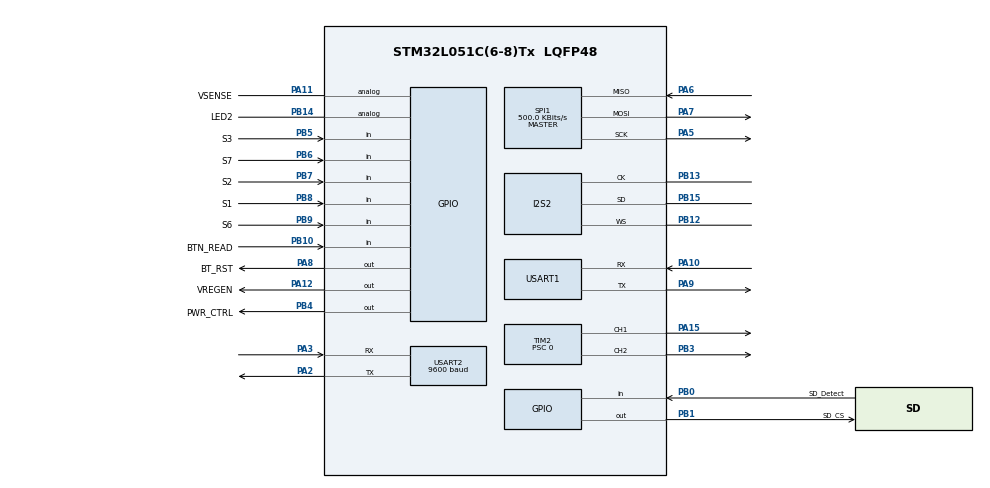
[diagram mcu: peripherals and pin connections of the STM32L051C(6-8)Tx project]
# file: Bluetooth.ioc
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Dma.Request0=SPI1_RX
Dma.Request1=SPI2_TX
Dma.SPI1_RX.0.Direction=DMA_PERIPH_TO_MEMORY
Dma.SPI1_RX.0.Instance=DMA1_Channel2
Dma.SPI1_RX.0.MemDataAlignment=DMA_MDATAALIGN_BYTE
Dma.SPI1_RX.0.MemInc=DMA_MINC_ENABLE
Dma.SPI1_RX.0.Mode=DMA_NORMAL
Dma.SPI1_RX.0.PeriphDataAlignment=DMA_PDATAALIGN_BYTE
Dma.SPI1_RX.0.PeriphInc=DMA_PINC_DISABLE
Dma.SPI1_RX.0.Priority=DMA_PRIORITY_HIGH
Dma.SPI2_TX.1.Direction=DMA_MEMORY_TO_PERIPH
Dma.SPI2_TX.1.Instance=DMA1_Channel5
Dma.SPI2_TX.1.MemDataAlignment=DMA_MDATAALIGN_BYTE
Dma.SPI2_TX.1.MemInc=DMA_MINC_ENABLE
Dma.SPI2_TX.1.Mode=DMA_NORMAL
Dma.SPI2_TX.1.PeriphDataAlignment=DMA_PDATAALIGN_BYTE
Dma.SPI2_TX.1.PeriphInc=DMA_PINC_DISABLE
Dma.SPI2_TX.1.Priority=DMA_PRIORITY_HIGH
FATFS._FS_MINIMIZE=0
FATFS._USE_MKFS=0
I2S2.AudioFreq=I2S_AUDIOFREQ_44K
I2S2.ErrorAudioFreq=-5.3 %
I2S2.Instance=SPI$Index
I2S2.RealAudioFreq=41.666 KHz
I2S2.Standard=I2S_STANDARD_PCM_SHORT
I2S2.VirtualMode=I2S_MODE_SLAVE
Mcu.Family=STM32L0
Mcu.Name=STM32L051C(6-8)Tx
Mcu.Package=LQFP48
NVIC.DMA1_Channel2_3_IRQn=true\:0\:0\:false\:false\:true\:false
NVIC.DMA1_Channel4_5_6_7_IRQn=true\:0\:0\:false\:false\:true\:false
NVIC.TIM2_IRQn=true\:0\:0\:false\:false\:true\:true
NVIC.USART1_IRQn=true\:0\:0\:false\:false\:true\:true
PA10.Mode=Asynchronous
PA10.Signal=USART1_RX
PA11.GPIO_Label=VSENSE
PA11.Signal=GPIO_Analog
PA12.GPIO_Label=VREGEN
PA12.Signal=GPIO_Output
PA13.Mode=Serial_Wire
PA13.Signal=SYS_SWDIO
PA14.Mode=Serial_Wire
PA14.Signal=SYS_SWCLK
PA15.Signal=S_TIM2_CH1
PA2.Mode=Asynchronous
PA2.Signal=USART2_TX
PA3.Mode=Asynchronous
PA3.Signal=USART2_RX
PA5.Mode=Full_Duplex_Master
PA5.Signal=SPI1_SCK
PA6.Mode=Full_Duplex_Master
PA6.Signal=SPI1_MISO
PA7.Mode=Full_Duplex_Master
PA7.Signal=SPI1_MOSI
PA8.GPIO_Label=BT_RST
PA8.Signal=GPIO_Output
PA9.Mode=Asynchronous
PA9.Signal=USART1_TX
PB0.GPIO_Label=SD_Detect
PB0.GPIO_PuPd=GPIO_PULLUP
PB0.Signal=GPIO_Input
PB1.GPIO_Label=SD_CS
PB1.PinState=GPIO_PIN_RESET
PB1.Signal=GPIO_Output
PB10.GPIO_Label=BTN_READ
PB10.GPIO_PuPd=GPIO_PULLUP
PB10.Signal=GPIO_Input
PB12.Mode=Half_Duplex_Slave
PB12.Signal=I2S2_WS
PB13.Mode=Half_Duplex_Slave
PB13.Signal=I2S2_CK
PB14.GPIO_Label=LED2
PB14.Signal=GPIO_Analog
PB15.Mode=Half_Duplex_Slave
PB15.Signal=I2S2_SD
PB3.Signal=S_TIM2_CH2
PB4.GPIO_Label=PWR_CTRL
PB4.Signal=GPIO_Output
PB5.GPIO_Label=S3
PB5.GPIO_PuPd=GPIO_PULLDOWN
PB5.Signal=GPIO_Input
PB6.GPIO_Label=S7
PB6.GPIO_PuPd=GPIO_PULLDOWN
PB6.Signal=GPIO_Input
PB7.GPIO_Label=S2
PB7.GPIO_PuPd=GPIO_PULLDOWN
PB7.Signal=GPIO_Input
PB8.GPIO_Label=S1
PB8.GPIO_PuPd=GPIO_PULLDOWN
PB8.Signal=GPIO_Input
PB9.GPIO_Label=S6
PB9.GPIO_PuPd=GPIO_PULLDOWN
PB9.Signal=GPIO_Input
ProjectManager.HeapSize=0x200
ProjectManager.StackSize=0x400
ProjectManager.TargetToolchain=TrueSTUDIO
RCC.ADCFreq_Value=4000000
RCC.AHBFreq_Value=8000000
RCC.APB1Freq_Value=8000000
RCC.APB1TimFreq_Value=8000000
RCC.APB2Freq_Value=8000000
RCC.APB2TimFreq_Value=8000000
RCC.HCLKFreq_Value=8000000
RCC.HSE_VALUE=8000000
RCC.HSI16_VALUE=16000000
RCC.HSIRCDiv=4
RCC.HSI_VALUE=4000000
RCC.LSE_VALUE=32768
RCC.MSI_VALUE=2097000
RCC.PLLMUL=RCC_PLLMUL_4
RCC.SYSCLKFreq_VALUE=8000000
RCC.SYSCLKSource=RCC_SYSCLKSOURCE_PLLCLK
RCC.VCOOutputFreq_Value=16000000
SH.S_TIM2_CH1.0=TIM2_CH1,PWM Generation1 CH1
SH.S_TIM2_CH2.0=TIM2_CH2,PWM Generation2 CH2
SPI1.BaudRatePrescaler=SPI_BAUDRATEPRESCALER_16
SPI1.CalculateBaudRate=500.0 KBits/s
SPI1.Direction=SPI_DIRECTION_2LINES
SPI1.Mode=SPI_MODE_MASTER
SPI1.VirtualType=VM_MASTER
TIM2.AutoReloadPreload=TIM_AUTORELOAD_PRELOAD_ENABLE
TIM2.Channel-PWM\ Generation1\ CH1=TIM_CHANNEL_1
TIM2.Channel-PWM\ Generation2\ CH2=TIM_CHANNEL_2
TIM2.OCMode_PWM-PWM\ Generation1\ CH1=TIM_OCMODE_PWM1
TIM2.Period=799
TIM2.Prescaler=0
TIM2.Pulse-PWM\ Generation1\ CH1=10
TIM2.Pulse-PWM\ Generation2\ CH2=10
USART1.VirtualMode-Asynchronous=VM_ASYNC
USART2.BaudRate=9600
USART2.VirtualMode-Asynchronous=VM_ASYNC
VP_FATFS_VS_Generic.Mode=User_defined
VP_TIM2_VS_ClockSourceINT.Mode=Internal
board=custom

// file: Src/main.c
/* USER CODE BEGIN Header */
/**
  ******************************************************************************
  * @file           : main.c
  * @brief          : Main program body
  ******************************************************************************
  * This notice applies to any and all portions of this file
  * that are not between comment pairs USER CODE BEGIN and
  * USER CODE END. Other portions of this file, whether
  * inserted by the user or by software development tools
  * are owned by their respective copyright owners.
  *
  * Copyright (c) 2019 STMicroelectronics International N.V.
  * All rights reserved.
  *
  * Redistribution and use in source and binary forms, with or without
  * modification, are permitted, provided that the following conditions are met:
  *
  * 1. Redistribution of source code must retain the above copyright notice,
  *    this list of conditions and the following disclaimer.
  * 2. Redistributions in binary form must reproduce the above copyright notice,
  *    this list of conditions and the following disclaimer in the documentation
  *    and/or other materials provided with the distribution.
  * 3. Neither the name of STMicroelectronics nor the names of other
  *    contributors to this software may be used to endorse or promote products
  *    derived from this software without specific written permission.
  * 4. This software, including modifications and/or derivative works of this
  *    software, must execute solely and exclusively on microcontroller or
  *    microprocessor devices manufactured by or for STMicroelectronics.
  * 5. Redistribution and use of this software other than as permitted under
  *    this license is void and will automatically terminate your rights under
  *    this license.
  *
  * THIS SOFTWARE IS PROVIDED BY STMICROELECTRONICS AND CONTRIBUTORS "AS IS"
  * AND ANY EXPRESS, IMPLIED OR STATUTORY WARRANTIES, INCLUDING, BUT NOT
  * LIMITED TO, THE IMPLIED WARRANTIES OF MERCHANTABILITY, FITNESS FOR A
  * PARTICULAR PURPOSE AND NON-INFRINGEMENT OF THIRD PARTY INTELLECTUAL PROPERTY
  * RIGHTS ARE DISCLAIMED TO THE FULLEST EXTENT PERMITTED BY LAW. IN NO EVENT
  * SHALL STMICROELECTRONICS OR CONTRIBUTORS BE LIABLE FOR ANY DIRECT, INDIRECT,
  * INCIDENTAL, SPECIAL, EXEMPLARY, OR CONSEQUENTIAL DAMAGES (INCLUDING, BUT NOT
  * LIMITED TO, PROCUREMENT OF SUBSTITUTE GOODS OR SERVICES; LOSS OF USE, DATA,
  * OR PROFITS; OR BUSINESS INTERRUPTION) HOWEVER CAUSED AND ON ANY THEORY OF
  * LIABILITY, WHETHER IN CONTRACT, STRICT LIABILITY, OR TORT (INCLUDING
  * NEGLIGENCE OR OTHERWISE) ARISING IN ANY WAY OUT OF THE USE OF THIS SOFTWARE,
  * EVEN IF ADVISED OF THE POSSIBILITY OF SUCH DAMAGE.
  *
  ******************************************************************************
  */
/* USER CODE END Header */

#include "main.h"

/* USER CODE BEGIN Includes */
#include <stdio.h>
#include <string.h>
#include <stdint.h>
#include "globals.h"
#include "AudioFile.h"
#include "fatfs.h"
#include "userInputs.h"
#include "stm32l0xx_hal.h"
#include "states.h"
#include "LEDControl.h"

/* USER CODE END Includes */

/* USER CODE BEGIN PV */
uint8_t usart1data;
uint8_t usart2data;
uint8_t bc127DataBuff[100];
uint8_t bc127DataBuffCt = 0;
uint8_t pcDataBuff[100];
uint8_t pcDataBuffCt = 0;
uint32_t initTickCount;
WAVaudioFile WAVfile;
bc127Device_t bc127Device;

bc127Notification_e Notification = INIT_STATE;
bc127Status_e Status = NOT_READY;

/* USER CODE END PV */

void SystemClock_Config(void);
static void MX_GPIO_Init(void);
static void MX_DMA_Init(void);
static void MX_SPI1_Init(void);
static void MX_I2S2_Init(void);
static void MX_USART1_UART_Init(void);
static void MX_USART2_UART_Init(void);
static void MX_TIM2_Init(void);
static void ADC_Init(void);

int main(void)
{

  /* MCU Configuration--------------------------------------------------------*/

  /* Reset of all peripherals, Initializes the Flash interface and the Systick. */
  HAL_Init();

  /* Configure the system clock */
  SystemClock_Config();

  /* Initialize all configured peripherals */
  MX_GPIO_Init();
  HAL_GPIO_WritePin(GPIOA,BT_RST_Pin,GPIO_PIN_SET); //this may be too late, may have to move this up as early as possible
  MX_DMA_Init();
  MX_SPI1_Init();
  MX_I2S2_Init();
  MX_USART1_UART_Init();
  MX_USART2_UART_Init();
  MX_FATFS_Init();
  MX_TIM2_Init();
  ADC_Init();

  /* USER CODE BEGIN 2 */
  timedStartup();
  sdInit();
  /* USER CODE END 2 */

  /* Infinite loop */
  while (1)
  {

    /* USER CODE BEGIN 3 */
	  runStates(&WAVfile, &bc127Device);

	  LEDBlinkControl(&bc127Device);

	  if(HAL_GPIO_ReadPin(GPIOB,BTN_READ_Pin) == GPIO_PIN_RESET){
			 HAL_GPIO_WritePin(GPIOB,PWR_CTRL_Pin,GPIO_PIN_RESET);
	  }

	  usartHandler();
	  bc127UartHandler();
	  bc127Read(&bc127Device);
	  checkButtonPresses();
  }
  /* USER CODE END 3 */
}

void SystemClock_Config(void)
{
  RCC_OscInitTypeDef RCC_OscInitStruct = {0};
  RCC_ClkInitTypeDef RCC_ClkInitStruct = {0};
  RCC_PeriphCLKInitTypeDef PeriphClkInit = {0};

  /**Configure the main internal regulator output voltage
  */
  __HAL_PWR_VOLTAGESCALING_CONFIG(PWR_REGULATOR_VOLTAGE_SCALE1);
  /**Initializes the CPU, AHB and APB busses clocks
  */
  RCC_OscInitStruct.OscillatorType = RCC_OSCILLATORTYPE_HSI;
  //RCC_OscInitStruct.HSIState = RCC_HSI_DIV4;
  RCC_OscInitStruct.HSIState = RCC_HSI_ON;
  RCC_OscInitStruct.HSICalibrationValue = RCC_HSICALIBRATION_DEFAULT;
  RCC_OscInitStruct.PLL.PLLState = RCC_PLL_ON;
  RCC_OscInitStruct.PLL.PLLSource = RCC_PLLSOURCE_HSI;
  RCC_OscInitStruct.PLL.PLLMUL = RCC_PLLMUL_6;
  RCC_OscInitStruct.PLL.PLLDIV = RCC_PLLDIV_4;
  //RCC_OscInitStruct.PLL.PLLDIV = RCC_PLLDIV_4; //this combined with HSI state brings f to 16MHz
  if (HAL_RCC_OscConfig(&RCC_OscInitStruct) != HAL_OK)
  {
    Error_Handler();
  }
  /**Initializes the CPU, AHB and APB busses clocks
  */
  RCC_ClkInitStruct.ClockType = RCC_CLOCKTYPE_HCLK|RCC_CLOCKTYPE_SYSCLK
                              |RCC_CLOCKTYPE_PCLK1|RCC_CLOCKTYPE_PCLK2;
  RCC_ClkInitStruct.SYSCLKSource = RCC_SYSCLKSOURCE_PLLCLK;
  RCC_ClkInitStruct.AHBCLKDivider = RCC_SYSCLK_DIV1;
  RCC_ClkInitStruct.APB1CLKDivider = RCC_HCLK_DIV1;
  RCC_ClkInitStruct.APB2CLKDivider = RCC_HCLK_DIV1;

  if (HAL_RCC_ClockConfig(&RCC_ClkInitStruct, FLASH_LATENCY_0) != HAL_OK)
  {
    Error_Handler();
  }
  PeriphClkInit.PeriphClockSelection = RCC_PERIPHCLK_USART1|RCC_PERIPHCLK_USART2;
  PeriphClkInit.Usart1ClockSelection = RCC_USART1CLKSOURCE_PCLK2;
  PeriphClkInit.Usart2ClockSelection = RCC_USART2CLKSOURCE_PCLK1;
  if (HAL_RCCEx_PeriphCLKConfig(&PeriphClkInit) != HAL_OK)
  {
    Error_Handler();
  }
}

static void MX_I2S2_Init(void)
{

  hi2s2.Instance = SPI2;
  hi2s2.Init.Mode = I2S_MODE_MASTER_TX;
  hi2s2.Init.Standard = I2S_STANDARD_PHILIPS;
  hi2s2.Init.DataFormat = I2S_DATAFORMAT_16B_EXTENDED;
  hi2s2.Init.MCLKOutput = I2S_MCLKOUTPUT_DISABLE;
  hi2s2.Init.AudioFreq = I2S_AUDIOFREQ_48K;
  hi2s2.Init.CPOL = I2S_CPOL_LOW;
  if (HAL_I2S_Init(&hi2s2) != HAL_OK)
  {
    Error_Handler();
  }
  /* USER CODE BEGIN I2S2_Init 2 */
  HAL_I2S_MspInit(&hi2s2);
  /* USER CODE END I2S2_Init 2 */

}

/*
  * @brief TIM2 Initialization Function
  * @param None
  * @retval None
  */
static void MX_TIM2_Init(void)
{

  TIM_ClockConfigTypeDef sClockSourceConfig = {0};
  TIM_MasterConfigTypeDef sMasterConfig = {0};
  TIM_OC_InitTypeDef sConfigOC = {0};

  htim2.Instance = TIM2;
  htim2.Init.Prescaler = 0;
  htim2.Init.CounterMode = TIM_COUNTERMODE_UP;
  htim2.Init.Period = 799;
  htim2.Init.ClockDivision = TIM_CLOCKDIVISION_DIV1;
  htim2.Init.AutoReloadPreload = TIM_AUTORELOAD_PRELOAD_ENABLE;
  if (HAL_TIM_Base_Init(&htim2) != HAL_OK)
  {
    Error_Handler();
  }
  sClockSourceConfig.ClockSource = TIM_CLOCKSOURCE_INTERNAL;
  if (HAL_TIM_ConfigClockSource(&htim2, &sClockSourceConfig) != HAL_OK)
  {
    Error_Handler();
  }
  if (HAL_TIM_PWM_Init(&htim2) != HAL_OK)
  {
    Error_Handler();
  }
  sMasterConfig.MasterOutputTrigger = TIM_TRGO_RESET;
  sMasterConfig.MasterSlaveMode = TIM_MASTERSLAVEMODE_DISABLE;
  if (HAL_TIMEx_MasterConfigSynchronization(&htim2, &sMasterConfig) != HAL_OK)
  {
    Error_Handler();
  }
  sConfigOC.OCMode = TIM_OCMODE_PWM1;
  sConfigOC.Pulse = 10;
  sConfigOC.OCPolarity = TIM_OCPOLARITY_HIGH;
  sConfigOC.OCFastMode = TIM_OCFAST_DISABLE;
  if (HAL_TIM_PWM_ConfigChannel(&htim2, &sConfigOC, TIM_CHANNEL_1) != HAL_OK)
  {
    Error_Handler();
  }
  if (HAL_TIM_PWM_ConfigChannel(&htim2, &sConfigOC, TIM_CHANNEL_2) != HAL_OK)
  {
    Error_Handler();
  }
  HAL_TIM_MspPostInit(&htim2);

}

static void MX_USART1_UART_Init(void)
{

  huart1.Instance = USART1;
  huart1.Init.BaudRate = 115200;
  huart1.Init.WordLength = UART_WORDLENGTH_8B;
  huart1.Init.StopBits = UART_STOPBITS_1;
  huart1.Init.Parity = UART_PARITY_NONE;
  huart1.Init.Mode = UART_MODE_TX_RX;
  huart1.Init.HwFlowCtl = UART_HWCONTROL_NONE;
  huart1.Init.OverSampling = UART_OVERSAMPLING_16;
  huart1.Init.OneBitSampling = UART_ONE_BIT_SAMPLE_DISABLE;
  huart1.AdvancedInit.AdvFeatureInit = UART_ADVFEATURE_NO_INIT;
  if (HAL_UART_Init(&huart1) != HAL_OK)
  {
    Error_Handler();
  }
  /* USER CODE BEGIN USART1_Init 2 */
  USART1->CR1 = (USART1->CR1) | (USART_CR1_RXNEIE);//RX not empty interrupt enable
  /* USER CODE END USART1_Init 2 */

}
static void MX_USART2_UART_Init(void)
{

  huart2.Instance = USART2;
  huart2.Init.BaudRate = 9600;
  huart2.Init.WordLength = UART_WORDLENGTH_8B;
  huart2.Init.StopBits = UART_STOPBITS_1;
  huart2.Init.Parity = UART_PARITY_NONE;
  huart2.Init.Mode = UART_MODE_TX_RX;
  huart2.Init.HwFlowCtl = UART_HWCONTROL_NONE;
  huart2.Init.OverSampling = UART_OVERSAMPLING_16;
  huart2.Init.OneBitSampling = UART_ONE_BIT_SAMPLE_DISABLE;
  huart2.AdvancedInit.AdvFeatureInit = UART_ADVFEATURE_NO_INIT;
  if (HAL_UART_Init(&huart2) != HAL_OK)
  {
    Error_Handler();
  }
  /* USER CODE BEGIN USART2_Init 2 */
  USART2->CR1 = (USART2->CR1) | (USART_CR1_RXNEIE);//RX not empty interrupt enable
  /* USER CODE END USART2_Init 2 */

}

static void MX_DMA_Init(void)
{
  /* DMA controller clock enable */
  __HAL_RCC_DMA1_CLK_ENABLE();

  /* DMA interrupt init */
  /* DMA1_Channel2_3_IRQn interrupt configuration */
  HAL_NVIC_SetPriority(DMA1_Channel2_3_IRQn, 1, 0);
  HAL_NVIC_EnableIRQ(DMA1_Channel2_3_IRQn);
  /* DMA1_Channel4_5_6_7_IRQn interrupt configuration */
  HAL_NVIC_SetPriority(DMA1_Channel4_5_6_7_IRQn, 0, 0);
  HAL_NVIC_EnableIRQ(DMA1_Channel4_5_6_7_IRQn);

}

static void  MX_SPI1_Init(void)
{

  /* SPI1 parameter configuration*/
  hspi1.Instance = SPI1;
  hspi1.Init.Mode = SPI_MODE_MASTER;
  hspi1.Init.Direction = SPI_DIRECTION_2LINES;
  hspi1.Init.DataSize = SPI_DATASIZE_8BIT;
  hspi1.Init.CLKPolarity = SPI_POLARITY_LOW;
  hspi1.Init.CLKPhase = SPI_PHASE_1EDGE;
  hspi1.Init.NSS = SPI_NSS_SOFT;
  hspi1.Init.BaudRatePrescaler = SPI_BAUDRATEPRESCALER_256;
  hspi1.Init.FirstBit = SPI_FIRSTBIT_MSB;
  hspi1.Init.TIMode = SPI_TIMODE_DISABLE;
  hspi1.Init.CRCCalculation = SPI_CRCCALCULATION_DISABLE;
  hspi1.Init.CRCPolynomial = 10;
  if (HAL_SPI_Init(&hspi1) != HAL_OK)
  {
    Error_Handler();
  }
  /* USER CODE BEGIN SPI1_Init 2 */
  HAL_SPI_MspInit(&hspi1);
  /* USER CODE END SPI1_Init 2 */

}

static void MX_GPIO_Init(void)
{
  GPIO_InitTypeDef GPIO_InitStruct = {0};

  /* GPIO Ports Clock Enable */
  __HAL_RCC_GPIOA_CLK_ENABLE();
  __HAL_RCC_GPIOB_CLK_ENABLE();

  /*Configure GPIO pin Output Level */
  HAL_GPIO_WritePin(GPIOB, SD_CS_Pin|PWR_CTRL_Pin, GPIO_PIN_RESET);

  /*Configure GPIO pin Output Level */
  HAL_GPIO_WritePin(GPIOA, BT_RST_Pin|VREGEN_Pin, GPIO_PIN_RESET);

  /*Configure GPIO pins : SD_Detect_Pin BTN_READ_Pin */
  GPIO_InitStruct.Pin = SD_Detect_Pin|BTN_READ_Pin;
  GPIO_InitStruct.Mode = GPIO_MODE_INPUT;
  GPIO_InitStruct.Pull = GPIO_PULLUP;
  HAL_GPIO_Init(GPIOB, &GPIO_InitStruct);

  /*Configure GPIO pins : SD_CS_Pin PWR_CTRL_Pin */
  GPIO_InitStruct.Pin = SD_CS_Pin|PWR_CTRL_Pin;
  GPIO_InitStruct.Mode = GPIO_MODE_OUTPUT_PP;
  GPIO_InitStruct.Pull = GPIO_NOPULL;
  GPIO_InitStruct.Speed = GPIO_SPEED_FREQ_LOW;
  HAL_GPIO_Init(GPIOB, &GPIO_InitStruct);

  /*Configure GPIO pin : LED2_Pin */
  GPIO_InitStruct.Pin = LED2_Pin;
  GPIO_InitStruct.Mode = GPIO_MODE_OUTPUT_PP;
  GPIO_InitStruct.Pull = GPIO_NOPULL;
  GPIO_InitStruct.Speed  = GPIO_SPEED_FREQ_LOW;
  HAL_GPIO_Init(LED2_GPIO_Port, &GPIO_InitStruct);

  /*Configure GPIO pins : BT_RST_Pin VREGEN_Pin */
  GPIO_InitStruct.Pin = BT_RST_Pin|VREGEN_Pin;
  GPIO_InitStruct.Mode = GPIO_MODE_OUTPUT_PP;
  GPIO_InitStruct.Pull = GPIO_NOPULL;
  GPIO_InitStruct.Speed = GPIO_SPEED_FREQ_LOW;
  HAL_GPIO_Init(GPIOA, &GPIO_InitStruct);

  /*Configure GPIO pin : VSENSE_Pin */
  GPIO_InitStruct.Pin = VSENSE_Pin;
  GPIO_InitStruct.Mode = GPIO_MODE_ANALOG;
  GPIO_InitStruct.Pull = GPIO_NOPULL;
  HAL_GPIO_Init(VSENSE_GPIO_Port, &GPIO_InitStruct);

  /*Configure GPIO pins : S3_Pin S7_Pin S2_Pin S1_Pin
                           S6_Pin */
  GPIO_InitStruct.Pin = S3_Pin|S7_Pin|S2_Pin|S1_Pin
                          |S6_Pin;
  GPIO_InitStruct.Mode = GPIO_MODE_INPUT;
  GPIO_InitStruct.Pull = GPIO_PULLDOWN;
  HAL_GPIO_Init(GPIOB, &GPIO_InitStruct);

}

/* USER CODE BEGIN 4 */

void ADC_Init(void)
{/*
	hadc1.Init = ADC;
	hadc1.

  if (HAL_ADC_Init(&hadc1) != HAL_OK)
  {
	Error_Handler();
  }*/
}
void usartHandler(void)
{
	if(usart1data)
	{

	  if(usart1data != 0x0d){
		  pcDataBuff[pcDataBuffCt] = usart1data;
		  usart1data = 0;
		  pcDataBuffCt++;
	  }

	  if(usart1data == 0x0D){
		  pcDataBuff[pcDataBuffCt] = 0x0d;
		  HAL_UART_Transmit(&huart2,pcDataBuff,(pcDataBuffCt+1),1000);
		  printf("\n\n");
		  usart1data = 0;
		  memset(pcDataBuff, 0, 100);
		  pcDataBuffCt = 0;
	  }
  }
}

void HAL_I2S_ErrorCallback(I2S_HandleTypeDef *hi2s)
{
	printf("I2S Error\r\n");
}

void timedStartup(void)
{
	printf("~~~~~ MCU Initialized ~~~~~\r\n");
	HAL_GPIO_WritePin(GPIOB,PWR_CTRL_Pin,GPIO_PIN_SET);

	HAL_TIM_Base_Start(&htim2);

	HAL_TIM_PWM_Start_IT(&htim2,TIM_CHANNEL_1);
	HAL_TIM_PWM_Start_IT(&htim2,TIM_CHANNEL_2);

	HAL_GPIO_WritePin(GPIOA,VREGEN_Pin,GPIO_PIN_RESET); //should boot to low anyway but be sure to force it here just in case
	initTickCount = HAL_GetTick();

	while(HAL_GetTick() < (initTickCount + 5)){} //keeps VREGEN low for +5ms then goes high
	HAL_GPIO_WritePin(GPIOA,VREGEN_Pin,GPIO_PIN_SET);

	while(HAL_GetTick() < (initTickCount + 10)){} //keeps reset high for +10ms then goes low
	HAL_GPIO_WritePin(GPIOA,BT_RST_Pin,GPIO_PIN_RESET);

	while(HAL_GetTick() < (initTickCount + 30)){} //keeps reset low for 20ms then goes high
	HAL_GPIO_WritePin(GPIOA,BT_RST_Pin,GPIO_PIN_SET);

	while(HAL_GetTick() < (initTickCount + 50)){}
	HAL_GPIO_WritePin(GPIOA,VREGEN_Pin,GPIO_PIN_RESET);

	HAL_TIM_PWM_Stop_IT(&htim2,TIM_CHANNEL_1);
	HAL_TIM_PWM_Stop_IT(&htim2,TIM_CHANNEL_2);

	HAL_UART_Transmit(&huart2,(uint8_t*)"RESET\r",6,1000);
}
/* USER CODE END 4 */

/************************ (C) COPYRIGHT STMicroelectronics *****END OF FILE****/
